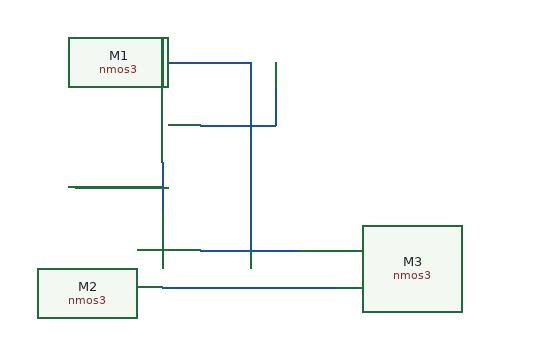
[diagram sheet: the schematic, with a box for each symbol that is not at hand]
v {xschem version=3.4.3 file_version=1.2
}
G {}
K {}
V {}
S {}
E {}
N 0 30 0 70 {
lab=#net1}
N 30 100 110 100 {
lab=#net2}
N 0 130 140 130 {
lab=#net3}
N 70 50 70 100 {}
N 70 -50 70 50 {}
N 0 -50 70 -50 {}
N 0 -50 0 -30 {}
N -0 -70 -0 -50 {}
N 30 -0 90 -0 {}
N 90 -50 90 -0 {}
N -70 50 0 50 {}
C {madvlsi/nmos3.sym} 0 0 0 1 {name=M1
L=0.5
W=12
body=GND
nf=1
mult=1
ad="'int((nf+1)/2) * W/nf * 0.29'" 
pd="'2*int((nf+1)/2) * (W/nf + 0.29)'"
as="'int((nf+2)/2) * W/nf * 0.29'" 
ps="'2*int((nf+2)/2) * (W/nf + 0.29)'"
nrd="'0.29 / W'" nrs="'0.29 / W'"
sa=0 sb=0 sd=0
model=nfet_01v8
spiceprefix=X
}
C {madvlsi/nmos3.sym} 0 100 0 1 {name=M2
L=0.5
W=12
body=GND
nf=1
mult=1
ad="'int((nf+1)/2) * W/nf * 0.29'" 
pd="'2*int((nf+1)/2) * (W/nf + 0.29)'"
as="'int((nf+2)/2) * W/nf * 0.29'" 
ps="'2*int((nf+2)/2) * (W/nf + 0.29)'"
nrd="'0.29 / W'" nrs="'0.29 / W'"
sa=0 sb=0 sd=0
model=nfet_01v8
spiceprefix=X
}
C {madvlsi/nmos3.sym} 140 100 0 0 {name=M3
L=0.5
W=12
body=GND
nf=1
mult=1
ad="'int((nf+1)/2) * W/nf * 0.29'" 
pd="'2*int((nf+1)/2) * (W/nf + 0.29)'"
as="'int((nf+2)/2) * W/nf * 0.29'" 
ps="'2*int((nf+2)/2) * (W/nf + 0.29)'"
nrd="'0.29 / W'" nrs="'0.29 / W'"
sa=0 sb=0 sd=0
model=nfet_01v8
spiceprefix=X
}
